# OpenTallas memory compiler (tools/mem_compiler), ASAP7 abstract view
VERSION 5.7 ;
BUSBITCHARS "[]" ;
DIVIDERCHAR "/" ;
PROPERTYDEFINITIONS
  MACRO width INTEGER ;
  MACRO depth INTEGER ;
  MACRO banks INTEGER ;
END PROPERTYDEFINITIONS
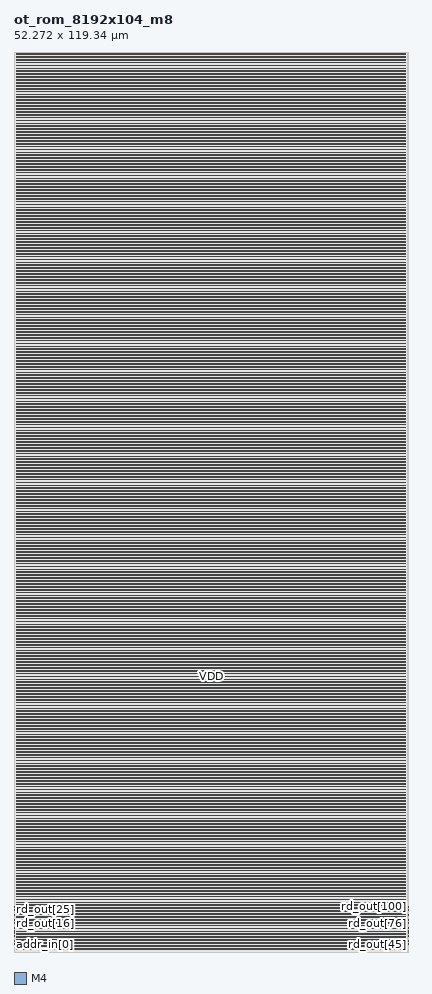
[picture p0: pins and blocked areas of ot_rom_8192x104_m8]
MACRO ot_rom_8192x104_m8
  PROPERTY width 104 ;
  PROPERTY depth 8192 ;
  PROPERTY banks 1 ;
  FOREIGN ot_rom_8192x104_m8 0 0 ;
  SYMMETRY X Y R90 ;
  SIZE 52.272 BY 119.340 ;
  CLASS BLOCK ;
  PIN clk
    DIRECTION INPUT ;
    USE CLOCK ;
    SHAPE ABUTMENT ;
    PORT
      LAYER M4 ;
      RECT 0.000 0.768 0.024 0.792 ;
    END
  END clk
  PIN ce_in
    DIRECTION INPUT ;
    USE SIGNAL ;
    SHAPE ABUTMENT ;
    PORT
      LAYER M4 ;
      RECT 0.000 0.864 0.024 0.888 ;
    END
  END ce_in
  PIN addr_in[0]
    DIRECTION INPUT ;
    USE SIGNAL ;
    SHAPE ABUTMENT ;
    PORT
      LAYER M4 ;
      RECT 0.000 0.960 0.024 0.984 ;
    END
  END addr_in[0]
  PIN addr_in[1]
    DIRECTION INPUT ;
    USE SIGNAL ;
    SHAPE ABUTMENT ;
    PORT
      LAYER M4 ;
      RECT 0.000 1.056 0.024 1.080 ;
    END
  END addr_in[1]
  PIN addr_in[2]
    DIRECTION INPUT ;
    USE SIGNAL ;
    SHAPE ABUTMENT ;
    PORT
      LAYER M4 ;
      RECT 0.000 1.152 0.024 1.176 ;
    END
  END addr_in[2]
  PIN addr_in[3]
    DIRECTION INPUT ;
    USE SIGNAL ;
    SHAPE ABUTMENT ;
    PORT
      LAYER M4 ;
      RECT 0.000 1.248 0.024 1.272 ;
    END
  END addr_in[3]
  PIN addr_in[4]
    DIRECTION INPUT ;
    USE SIGNAL ;
    SHAPE ABUTMENT ;
    PORT
      LAYER M4 ;
      RECT 0.000 1.344 0.024 1.368 ;
    END
  END addr_in[4]
  PIN addr_in[5]
    DIRECTION INPUT ;
    USE SIGNAL ;
    SHAPE ABUTMENT ;
    PORT
      LAYER M4 ;
      RECT 0.000 1.440 0.024 1.464 ;
    END
  END addr_in[5]
  PIN addr_in[6]
    DIRECTION INPUT ;
    USE SIGNAL ;
    SHAPE ABUTMENT ;
    PORT
      LAYER M4 ;
      RECT 0.000 1.536 0.024 1.560 ;
    END
  END addr_in[6]
  PIN addr_in[7]
    DIRECTION INPUT ;
    USE SIGNAL ;
    SHAPE ABUTMENT ;
    PORT
      LAYER M4 ;
      RECT 0.000 1.632 0.024 1.656 ;
    END
  END addr_in[7]
  PIN addr_in[8]
    DIRECTION INPUT ;
    USE SIGNAL ;
    SHAPE ABUTMENT ;
    PORT
      LAYER M4 ;
      RECT 0.000 1.728 0.024 1.752 ;
    END
  END addr_in[8]
  PIN addr_in[9]
    DIRECTION INPUT ;
    USE SIGNAL ;
    SHAPE ABUTMENT ;
    PORT
      LAYER M4 ;
      RECT 0.000 1.824 0.024 1.848 ;
    END
  END addr_in[9]
  PIN addr_in[10]
    DIRECTION INPUT ;
    USE SIGNAL ;
    SHAPE ABUTMENT ;
    PORT
      LAYER M4 ;
      RECT 0.000 1.920 0.024 1.944 ;
    END
  END addr_in[10]
  PIN addr_in[11]
    DIRECTION INPUT ;
    USE SIGNAL ;
    SHAPE ABUTMENT ;
    PORT
      LAYER M4 ;
      RECT 0.000 2.016 0.024 2.040 ;
    END
  END addr_in[11]
  PIN addr_in[12]
    DIRECTION INPUT ;
    USE SIGNAL ;
    SHAPE ABUTMENT ;
    PORT
      LAYER M4 ;
      RECT 0.000 2.112 0.024 2.136 ;
    END
  END addr_in[12]
  PIN rd_out[0]
    DIRECTION OUTPUT ;
    USE SIGNAL ;
    SHAPE ABUTMENT ;
    PORT
      LAYER M4 ;
      RECT 0.000 2.208 0.024 2.232 ;
    END
  END rd_out[0]
  PIN rd_out[1]
    DIRECTION OUTPUT ;
    USE SIGNAL ;
    SHAPE ABUTMENT ;
    PORT
      LAYER M4 ;
      RECT 0.000 2.304 0.024 2.328 ;
    END
  END rd_out[1]
  PIN rd_out[2]
    DIRECTION OUTPUT ;
    USE SIGNAL ;
    SHAPE ABUTMENT ;
    PORT
      LAYER M4 ;
      RECT 0.000 2.400 0.024 2.424 ;
    END
  END rd_out[2]
  PIN rd_out[3]
    DIRECTION OUTPUT ;
    USE SIGNAL ;
    SHAPE ABUTMENT ;
    PORT
      LAYER M4 ;
      RECT 0.000 2.496 0.024 2.520 ;
    END
  END rd_out[3]
  PIN rd_out[4]
    DIRECTION OUTPUT ;
    USE SIGNAL ;
    SHAPE ABUTMENT ;
    PORT
      LAYER M4 ;
      RECT 0.000 2.592 0.024 2.616 ;
    END
  END rd_out[4]
  PIN rd_out[5]
    DIRECTION OUTPUT ;
    USE SIGNAL ;
    SHAPE ABUTMENT ;
    PORT
      LAYER M4 ;
      RECT 0.000 2.688 0.024 2.712 ;
    END
  END rd_out[5]
  PIN rd_out[6]
    DIRECTION OUTPUT ;
    USE SIGNAL ;
    SHAPE ABUTMENT ;
    PORT
      LAYER M4 ;
      RECT 0.000 2.784 0.024 2.808 ;
    END
  END rd_out[6]
  PIN rd_out[7]
    DIRECTION OUTPUT ;
    USE SIGNAL ;
    SHAPE ABUTMENT ;
    PORT
      LAYER M4 ;
      RECT 0.000 2.880 0.024 2.904 ;
    END
  END rd_out[7]
  PIN rd_out[8]
    DIRECTION OUTPUT ;
    USE SIGNAL ;
    SHAPE ABUTMENT ;
    PORT
      LAYER M4 ;
      RECT 0.000 2.976 0.024 3.000 ;
    END
  END rd_out[8]
  PIN rd_out[9]
    DIRECTION OUTPUT ;
    USE SIGNAL ;
    SHAPE ABUTMENT ;
    PORT
      LAYER M4 ;
      RECT 0.000 3.072 0.024 3.096 ;
    END
  END rd_out[9]
  PIN rd_out[10]
    DIRECTION OUTPUT ;
    USE SIGNAL ;
    SHAPE ABUTMENT ;
    PORT
      LAYER M4 ;
      RECT 0.000 3.168 0.024 3.192 ;
    END
  END rd_out[10]
  PIN rd_out[11]
    DIRECTION OUTPUT ;
    USE SIGNAL ;
    SHAPE ABUTMENT ;
    PORT
      LAYER M4 ;
      RECT 0.000 3.264 0.024 3.288 ;
    END
  END rd_out[11]
  PIN rd_out[12]
    DIRECTION OUTPUT ;
    USE SIGNAL ;
    SHAPE ABUTMENT ;
    PORT
      LAYER M4 ;
      RECT 0.000 3.360 0.024 3.384 ;
    END
  END rd_out[12]
  PIN rd_out[13]
    DIRECTION OUTPUT ;
    USE SIGNAL ;
    SHAPE ABUTMENT ;
    PORT
      LAYER M4 ;
      RECT 0.000 3.456 0.024 3.480 ;
    END
  END rd_out[13]
  PIN rd_out[14]
    DIRECTION OUTPUT ;
    USE SIGNAL ;
    SHAPE ABUTMENT ;
    PORT
      LAYER M4 ;
      RECT 0.000 3.552 0.024 3.576 ;
    END
  END rd_out[14]
  PIN rd_out[15]
    DIRECTION OUTPUT ;
    USE SIGNAL ;
    SHAPE ABUTMENT ;
    PORT
      LAYER M4 ;
      RECT 0.000 3.648 0.024 3.672 ;
    END
  END rd_out[15]
  PIN rd_out[16]
    DIRECTION OUTPUT ;
    USE SIGNAL ;
    SHAPE ABUTMENT ;
    PORT
      LAYER M4 ;
      RECT 0.000 3.744 0.024 3.768 ;
    END
  END rd_out[16]
  PIN rd_out[17]
    DIRECTION OUTPUT ;
    USE SIGNAL ;
    SHAPE ABUTMENT ;
    PORT
      LAYER M4 ;
      RECT 0.000 3.840 0.024 3.864 ;
    END
  END rd_out[17]
  PIN rd_out[18]
    DIRECTION OUTPUT ;
    USE SIGNAL ;
    SHAPE ABUTMENT ;
    PORT
      LAYER M4 ;
      RECT 0.000 3.936 0.024 3.960 ;
    END
  END rd_out[18]
  PIN rd_out[19]
    DIRECTION OUTPUT ;
    USE SIGNAL ;
    SHAPE ABUTMENT ;
    PORT
      LAYER M4 ;
      RECT 0.000 4.032 0.024 4.056 ;
    END
  END rd_out[19]
  PIN rd_out[20]
    DIRECTION OUTPUT ;
    USE SIGNAL ;
    SHAPE ABUTMENT ;
    PORT
      LAYER M4 ;
      RECT 0.000 4.128 0.024 4.152 ;
    END
  END rd_out[20]
  PIN rd_out[21]
    DIRECTION OUTPUT ;
    USE SIGNAL ;
    SHAPE ABUTMENT ;
    PORT
      LAYER M4 ;
      RECT 0.000 4.224 0.024 4.248 ;
    END
  END rd_out[21]
  PIN rd_out[22]
    DIRECTION OUTPUT ;
    USE SIGNAL ;
    SHAPE ABUTMENT ;
    PORT
      LAYER M4 ;
      RECT 0.000 4.320 0.024 4.344 ;
    END
  END rd_out[22]
  PIN rd_out[23]
    DIRECTION OUTPUT ;
    USE SIGNAL ;
    SHAPE ABUTMENT ;
    PORT
      LAYER M4 ;
      RECT 0.000 4.416 0.024 4.440 ;
    END
  END rd_out[23]
  PIN rd_out[24]
    DIRECTION OUTPUT ;
    USE SIGNAL ;
    SHAPE ABUTMENT ;
    PORT
      LAYER M4 ;
      RECT 0.000 4.512 0.024 4.536 ;
    END
  END rd_out[24]
  PIN rd_out[25]
    DIRECTION OUTPUT ;
    USE SIGNAL ;
    SHAPE ABUTMENT ;
    PORT
      LAYER M4 ;
      RECT 0.000 4.608 0.024 4.632 ;
    END
  END rd_out[25]
  PIN rd_out[26]
    DIRECTION OUTPUT ;
    USE SIGNAL ;
    SHAPE ABUTMENT ;
    PORT
      LAYER M4 ;
      RECT 0.000 4.704 0.024 4.728 ;
    END
  END rd_out[26]
  PIN rd_out[27]
    DIRECTION OUTPUT ;
    USE SIGNAL ;
    SHAPE ABUTMENT ;
    PORT
      LAYER M4 ;
      RECT 0.000 4.800 0.024 4.824 ;
    END
  END rd_out[27]
  PIN rd_out[28]
    DIRECTION OUTPUT ;
    USE SIGNAL ;
    SHAPE ABUTMENT ;
    PORT
      LAYER M4 ;
      RECT 0.000 4.896 0.024 4.920 ;
    END
  END rd_out[28]
  PIN rd_out[29]
    DIRECTION OUTPUT ;
    USE SIGNAL ;
    SHAPE ABUTMENT ;
    PORT
      LAYER M4 ;
      RECT 0.000 4.992 0.024 5.016 ;
    END
  END rd_out[29]
  PIN rd_out[30]
    DIRECTION OUTPUT ;
    USE SIGNAL ;
    SHAPE ABUTMENT ;
    PORT
      LAYER M4 ;
      RECT 0.000 5.088 0.024 5.112 ;
    END
  END rd_out[30]
  PIN rd_out[31]
    DIRECTION OUTPUT ;
    USE SIGNAL ;
    SHAPE ABUTMENT ;
    PORT
      LAYER M4 ;
      RECT 0.000 5.184 0.024 5.208 ;
    END
  END rd_out[31]
  PIN rd_out[32]
    DIRECTION OUTPUT ;
    USE SIGNAL ;
    SHAPE ABUTMENT ;
    PORT
      LAYER M4 ;
      RECT 0.000 5.280 0.024 5.304 ;
    END
  END rd_out[32]
  PIN rd_out[33]
    DIRECTION OUTPUT ;
    USE SIGNAL ;
    SHAPE ABUTMENT ;
    PORT
      LAYER M4 ;
      RECT 0.000 5.376 0.024 5.400 ;
    END
  END rd_out[33]
  PIN rd_out[34]
    DIRECTION OUTPUT ;
    USE SIGNAL ;
    SHAPE ABUTMENT ;
    PORT
      LAYER M4 ;
      RECT 0.000 5.472 0.024 5.496 ;
    END
  END rd_out[34]
  PIN rd_out[35]
    DIRECTION OUTPUT ;
    USE SIGNAL ;
    SHAPE ABUTMENT ;
    PORT
      LAYER M4 ;
      RECT 0.000 5.568 0.024 5.592 ;
    END
  END rd_out[35]
  PIN rd_out[36]
    DIRECTION OUTPUT ;
    USE SIGNAL ;
    SHAPE ABUTMENT ;
    PORT
      LAYER M4 ;
      RECT 0.000 5.664 0.024 5.688 ;
    END
  END rd_out[36]
  PIN rd_out[37]
    DIRECTION OUTPUT ;
    USE SIGNAL ;
    SHAPE ABUTMENT ;
    PORT
      LAYER M4 ;
      RECT 0.000 5.760 0.024 5.784 ;
    END
  END rd_out[37]
  PIN rd_out[38]
    DIRECTION OUTPUT ;
    USE SIGNAL ;
    SHAPE ABUTMENT ;
    PORT
      LAYER M4 ;
      RECT 0.000 5.856 0.024 5.880 ;
    END
  END rd_out[38]
  PIN rd_out[39]
    DIRECTION OUTPUT ;
    USE SIGNAL ;
    SHAPE ABUTMENT ;
    PORT
      LAYER M4 ;
      RECT 0.000 5.952 0.024 5.976 ;
    END
  END rd_out[39]
  PIN rd_out[40]
    DIRECTION OUTPUT ;
    USE SIGNAL ;
    SHAPE ABUTMENT ;
    PORT
      LAYER M4 ;
      RECT 0.000 6.048 0.024 6.072 ;
    END
  END rd_out[40]
  PIN rd_out[41]
    DIRECTION OUTPUT ;
    USE SIGNAL ;
    SHAPE ABUTMENT ;
    PORT
      LAYER M4 ;
      RECT 0.000 6.144 0.024 6.168 ;
    END
  END rd_out[41]
  PIN rd_out[42]
    DIRECTION OUTPUT ;
    USE SIGNAL ;
    SHAPE ABUTMENT ;
    PORT
      LAYER M4 ;
      RECT 0.000 6.240 0.024 6.264 ;
    END
  END rd_out[42]
  PIN rd_out[43]
    DIRECTION OUTPUT ;
    USE SIGNAL ;
    SHAPE ABUTMENT ;
    PORT
      LAYER M4 ;
      RECT 0.000 6.336 0.024 6.360 ;
    END
  END rd_out[43]
  PIN rd_out[44]
    DIRECTION OUTPUT ;
    USE SIGNAL ;
    SHAPE ABUTMENT ;
    PORT
      LAYER M4 ;
      RECT 0.000 6.432 0.024 6.456 ;
    END
  END rd_out[44]
  PIN rd_out[45]
    DIRECTION OUTPUT ;
    USE SIGNAL ;
    SHAPE ABUTMENT ;
    PORT
      LAYER M4 ;
      RECT 52.248 0.768 52.272 0.792 ;
    END
  END rd_out[45]
  PIN rd_out[46]
    DIRECTION OUTPUT ;
    USE SIGNAL ;
    SHAPE ABUTMENT ;
    PORT
      LAYER M4 ;
      RECT 52.248 0.864 52.272 0.888 ;
    END
  END rd_out[46]
  PIN rd_out[47]
    DIRECTION OUTPUT ;
    USE SIGNAL ;
    SHAPE ABUTMENT ;
    PORT
      LAYER M4 ;
      RECT 52.248 0.960 52.272 0.984 ;
    END
  END rd_out[47]
  PIN rd_out[48]
    DIRECTION OUTPUT ;
    USE SIGNAL ;
    SHAPE ABUTMENT ;
    PORT
      LAYER M4 ;
      RECT 52.248 1.056 52.272 1.080 ;
    END
  END rd_out[48]
  PIN rd_out[49]
    DIRECTION OUTPUT ;
    USE SIGNAL ;
    SHAPE ABUTMENT ;
    PORT
      LAYER M4 ;
      RECT 52.248 1.152 52.272 1.176 ;
    END
  END rd_out[49]
  PIN rd_out[50]
    DIRECTION OUTPUT ;
    USE SIGNAL ;
    SHAPE ABUTMENT ;
    PORT
      LAYER M4 ;
      RECT 52.248 1.248 52.272 1.272 ;
    END
  END rd_out[50]
  PIN rd_out[51]
    DIRECTION OUTPUT ;
    USE SIGNAL ;
    SHAPE ABUTMENT ;
    PORT
      LAYER M4 ;
      RECT 52.248 1.344 52.272 1.368 ;
    END
  END rd_out[51]
  PIN rd_out[52]
    DIRECTION OUTPUT ;
    USE SIGNAL ;
    SHAPE ABUTMENT ;
    PORT
      LAYER M4 ;
      RECT 52.248 1.440 52.272 1.464 ;
    END
  END rd_out[52]
  PIN rd_out[53]
    DIRECTION OUTPUT ;
    USE SIGNAL ;
    SHAPE ABUTMENT ;
    PORT
      LAYER M4 ;
      RECT 52.248 1.536 52.272 1.560 ;
    END
  END rd_out[53]
  PIN rd_out[54]
    DIRECTION OUTPUT ;
    USE SIGNAL ;
    SHAPE ABUTMENT ;
    PORT
      LAYER M4 ;
      RECT 52.248 1.632 52.272 1.656 ;
    END
  END rd_out[54]
  PIN rd_out[55]
    DIRECTION OUTPUT ;
    USE SIGNAL ;
    SHAPE ABUTMENT ;
    PORT
      LAYER M4 ;
      RECT 52.248 1.728 52.272 1.752 ;
    END
  END rd_out[55]
  PIN rd_out[56]
    DIRECTION OUTPUT ;
    USE SIGNAL ;
    SHAPE ABUTMENT ;
    PORT
      LAYER M4 ;
      RECT 52.248 1.824 52.272 1.848 ;
    END
  END rd_out[56]
  PIN rd_out[57]
    DIRECTION OUTPUT ;
    USE SIGNAL ;
    SHAPE ABUTMENT ;
    PORT
      LAYER M4 ;
      RECT 52.248 1.920 52.272 1.944 ;
    END
  END rd_out[57]
  PIN rd_out[58]
    DIRECTION OUTPUT ;
    USE SIGNAL ;
    SHAPE ABUTMENT ;
    PORT
      LAYER M4 ;
      RECT 52.248 2.016 52.272 2.040 ;
    END
  END rd_out[58]
  PIN rd_out[59]
    DIRECTION OUTPUT ;
    USE SIGNAL ;
    SHAPE ABUTMENT ;
    PORT
      LAYER M4 ;
      RECT 52.248 2.112 52.272 2.136 ;
    END
  END rd_out[59]
  PIN rd_out[60]
    DIRECTION OUTPUT ;
    USE SIGNAL ;
    SHAPE ABUTMENT ;
    PORT
      LAYER M4 ;
      RECT 52.248 2.208 52.272 2.232 ;
    END
  END rd_out[60]
  PIN rd_out[61]
    DIRECTION OUTPUT ;
    USE SIGNAL ;
    SHAPE ABUTMENT ;
    PORT
      LAYER M4 ;
      RECT 52.248 2.304 52.272 2.328 ;
    END
  END rd_out[61]
  PIN rd_out[62]
    DIRECTION OUTPUT ;
    USE SIGNAL ;
    SHAPE ABUTMENT ;
    PORT
      LAYER M4 ;
      RECT 52.248 2.400 52.272 2.424 ;
    END
  END rd_out[62]
  PIN rd_out[63]
    DIRECTION OUTPUT ;
    USE SIGNAL ;
    SHAPE ABUTMENT ;
    PORT
      LAYER M4 ;
      RECT 52.248 2.496 52.272 2.520 ;
    END
  END rd_out[63]
  PIN rd_out[64]
    DIRECTION OUTPUT ;
    USE SIGNAL ;
    SHAPE ABUTMENT ;
    PORT
      LAYER M4 ;
      RECT 52.248 2.592 52.272 2.616 ;
    END
  END rd_out[64]
  PIN rd_out[65]
    DIRECTION OUTPUT ;
    USE SIGNAL ;
    SHAPE ABUTMENT ;
    PORT
      LAYER M4 ;
      RECT 52.248 2.688 52.272 2.712 ;
    END
  END rd_out[65]
  PIN rd_out[66]
    DIRECTION OUTPUT ;
    USE SIGNAL ;
    SHAPE ABUTMENT ;
    PORT
      LAYER M4 ;
      RECT 52.248 2.784 52.272 2.808 ;
    END
  END rd_out[66]
  PIN rd_out[67]
    DIRECTION OUTPUT ;
    USE SIGNAL ;
    SHAPE ABUTMENT ;
    PORT
      LAYER M4 ;
      RECT 52.248 2.880 52.272 2.904 ;
    END
  END rd_out[67]
  PIN rd_out[68]
    DIRECTION OUTPUT ;
    USE SIGNAL ;
    SHAPE ABUTMENT ;
    PORT
      LAYER M4 ;
      RECT 52.248 2.976 52.272 3.000 ;
    END
  END rd_out[68]
  PIN rd_out[69]
    DIRECTION OUTPUT ;
    USE SIGNAL ;
    SHAPE ABUTMENT ;
    PORT
      LAYER M4 ;
      RECT 52.248 3.072 52.272 3.096 ;
    END
  END rd_out[69]
  PIN rd_out[70]
    DIRECTION OUTPUT ;
    USE SIGNAL ;
    SHAPE ABUTMENT ;
    PORT
      LAYER M4 ;
      RECT 52.248 3.168 52.272 3.192 ;
    END
  END rd_out[70]
  PIN rd_out[71]
    DIRECTION OUTPUT ;
    USE SIGNAL ;
    SHAPE ABUTMENT ;
    PORT
      LAYER M4 ;
      RECT 52.248 3.264 52.272 3.288 ;
    END
  END rd_out[71]
  PIN rd_out[72]
    DIRECTION OUTPUT ;
    USE SIGNAL ;
    SHAPE ABUTMENT ;
    PORT
      LAYER M4 ;
      RECT 52.248 3.360 52.272 3.384 ;
    END
  END rd_out[72]
  PIN rd_out[73]
    DIRECTION OUTPUT ;
    USE SIGNAL ;
    SHAPE ABUTMENT ;
    PORT
      LAYER M4 ;
      RECT 52.248 3.456 52.272 3.480 ;
    END
  END rd_out[73]
  PIN rd_out[74]
    DIRECTION OUTPUT ;
    USE SIGNAL ;
    SHAPE ABUTMENT ;
    PORT
      LAYER M4 ;
      RECT 52.248 3.552 52.272 3.576 ;
    END
  END rd_out[74]
  PIN rd_out[75]
    DIRECTION OUTPUT ;
    USE SIGNAL ;
    SHAPE ABUTMENT ;
    PORT
      LAYER M4 ;
      RECT 52.248 3.648 52.272 3.672 ;
    END
  END rd_out[75]
  PIN rd_out[76]
    DIRECTION OUTPUT ;
    USE SIGNAL ;
    SHAPE ABUTMENT ;
    PORT
      LAYER M4 ;
      RECT 52.248 3.744 52.272 3.768 ;
    END
  END rd_out[76]
  PIN rd_out[77]
    DIRECTION OUTPUT ;
    USE SIGNAL ;
    SHAPE ABUTMENT ;
    PORT
      LAYER M4 ;
      RECT 52.248 3.840 52.272 3.864 ;
    END
  END rd_out[77]
  PIN rd_out[78]
    DIRECTION OUTPUT ;
    USE SIGNAL ;
    SHAPE ABUTMENT ;
    PORT
      LAYER M4 ;
      RECT 52.248 3.936 52.272 3.960 ;
    END
  END rd_out[78]
  PIN rd_out[79]
    DIRECTION OUTPUT ;
    USE SIGNAL ;
    SHAPE ABUTMENT ;
    PORT
      LAYER M4 ;
      RECT 52.248 4.032 52.272 4.056 ;
    END
  END rd_out[79]
  PIN rd_out[80]
    DIRECTION OUTPUT ;
    USE SIGNAL ;
    SHAPE ABUTMENT ;
    PORT
      LAYER M4 ;
      RECT 52.248 4.128 52.272 4.152 ;
    END
  END rd_out[80]
  PIN rd_out[81]
    DIRECTION OUTPUT ;
    USE SIGNAL ;
    SHAPE ABUTMENT ;
    PORT
      LAYER M4 ;
      RECT 52.248 4.224 52.272 4.248 ;
    END
  END rd_out[81]
  PIN rd_out[82]
    DIRECTION OUTPUT ;
    USE SIGNAL ;
    SHAPE ABUTMENT ;
    PORT
      LAYER M4 ;
      RECT 52.248 4.320 52.272 4.344 ;
    END
  END rd_out[82]
  PIN rd_out[83]
    DIRECTION OUTPUT ;
    USE SIGNAL ;
    SHAPE ABUTMENT ;
    PORT
      LAYER M4 ;
      RECT 52.248 4.416 52.272 4.440 ;
    END
  END rd_out[83]
  PIN rd_out[84]
    DIRECTION OUTPUT ;
    USE SIGNAL ;
    SHAPE ABUTMENT ;
    PORT
      LAYER M4 ;
      RECT 52.248 4.512 52.272 4.536 ;
    END
  END rd_out[84]
  PIN rd_out[85]
    DIRECTION OUTPUT ;
    USE SIGNAL ;
    SHAPE ABUTMENT ;
    PORT
      LAYER M4 ;
      RECT 52.248 4.608 52.272 4.632 ;
    END
  END rd_out[85]
  PIN rd_out[86]
    DIRECTION OUTPUT ;
    USE SIGNAL ;
    SHAPE ABUTMENT ;
    PORT
      LAYER M4 ;
      RECT 52.248 4.704 52.272 4.728 ;
    END
  END rd_out[86]
  PIN rd_out[87]
    DIRECTION OUTPUT ;
    USE SIGNAL ;
    SHAPE ABUTMENT ;
    PORT
      LAYER M4 ;
      RECT 52.248 4.800 52.272 4.824 ;
    END
  END rd_out[87]
  PIN rd_out[88]
    DIRECTION OUTPUT ;
    USE SIGNAL ;
    SHAPE ABUTMENT ;
    PORT
      LAYER M4 ;
      RECT 52.248 4.896 52.272 4.920 ;
    END
  END rd_out[88]
  PIN rd_out[89]
    DIRECTION OUTPUT ;
    USE SIGNAL ;
    SHAPE ABUTMENT ;
    PORT
      LAYER M4 ;
      RECT 52.248 4.992 52.272 5.016 ;
    END
  END rd_out[89]
  PIN rd_out[90]
    DIRECTION OUTPUT ;
    USE SIGNAL ;
    SHAPE ABUTMENT ;
    PORT
      LAYER M4 ;
      RECT 52.248 5.088 52.272 5.112 ;
    END
  END rd_out[90]
  PIN rd_out[91]
    DIRECTION OUTPUT ;
    USE SIGNAL ;
    SHAPE ABUTMENT ;
    PORT
      LAYER M4 ;
      RECT 52.248 5.184 52.272 5.208 ;
    END
  END rd_out[91]
  PIN rd_out[92]
    DIRECTION OUTPUT ;
    USE SIGNAL ;
    SHAPE ABUTMENT ;
    PORT
      LAYER M4 ;
      RECT 52.248 5.280 52.272 5.304 ;
    END
  END rd_out[92]
  PIN rd_out[93]
    DIRECTION OUTPUT ;
    USE SIGNAL ;
    SHAPE ABUTMENT ;
    PORT
      LAYER M4 ;
      RECT 52.248 5.376 52.272 5.400 ;
    END
  END rd_out[93]
  PIN rd_out[94]
    DIRECTION OUTPUT ;
    USE SIGNAL ;
    SHAPE ABUTMENT ;
    PORT
      LAYER M4 ;
      RECT 52.248 5.472 52.272 5.496 ;
    END
  END rd_out[94]
  PIN rd_out[95]
    DIRECTION OUTPUT ;
    USE SIGNAL ;
    SHAPE ABUTMENT ;
    PORT
      LAYER M4 ;
      RECT 52.248 5.568 52.272 5.592 ;
    END
  END rd_out[95]
  PIN rd_out[96]
    DIRECTION OUTPUT ;
    USE SIGNAL ;
    SHAPE ABUTMENT ;
    PORT
      LAYER M4 ;
      RECT 52.248 5.664 52.272 5.688 ;
    END
  END rd_out[96]
  PIN rd_out[97]
    DIRECTION OUTPUT ;
    USE SIGNAL ;
    SHAPE ABUTMENT ;
    PORT
      LAYER M4 ;
      RECT 52.248 5.760 52.272 5.784 ;
    END
  END rd_out[97]
  PIN rd_out[98]
    DIRECTION OUTPUT ;
    USE SIGNAL ;
    SHAPE ABUTMENT ;
    PORT
      LAYER M4 ;
      RECT 52.248 5.856 52.272 5.880 ;
    END
  END rd_out[98]
  PIN rd_out[99]
    DIRECTION OUTPUT ;
    USE SIGNAL ;
    SHAPE ABUTMENT ;
    PORT
      LAYER M4 ;
      RECT 52.248 5.952 52.272 5.976 ;
    END
  END rd_out[99]
  PIN rd_out[100]
    DIRECTION OUTPUT ;
    USE SIGNAL ;
    SHAPE ABUTMENT ;
    PORT
      LAYER M4 ;
      RECT 52.248 6.048 52.272 6.072 ;
    END
  END rd_out[100]
  PIN rd_out[101]
    DIRECTION OUTPUT ;
    USE SIGNAL ;
    SHAPE ABUTMENT ;
    PORT
      LAYER M4 ;
      RECT 52.248 6.144 52.272 6.168 ;
    END
  END rd_out[101]
  PIN rd_out[102]
    DIRECTION OUTPUT ;
    USE SIGNAL ;
    SHAPE ABUTMENT ;
    PORT
      LAYER M4 ;
      RECT 52.248 6.240 52.272 6.264 ;
    END
  END rd_out[102]
  PIN rd_out[103]
    DIRECTION OUTPUT ;
    USE SIGNAL ;
    SHAPE ABUTMENT ;
    PORT
      LAYER M4 ;
      RECT 52.248 6.336 52.272 6.360 ;
    END
  END rd_out[103]
  PIN VDD
    DIRECTION INOUT ;
    USE POWER ;
    PORT
      LAYER M4 ;
      RECT 0.300 0.384 51.972 0.480 ;
      RECT 0.300 1.152 51.972 1.248 ;
      RECT 0.300 1.920 51.972 2.016 ;
      RECT 0.300 2.688 51.972 2.784 ;
      RECT 0.300 3.456 51.972 3.552 ;
      RECT 0.300 4.224 51.972 4.320 ;
      RECT 0.300 4.992 51.972 5.088 ;
      RECT 0.300 5.760 51.972 5.856 ;
      RECT 0.300 6.528 51.972 6.624 ;
      RECT 0.300 7.296 51.972 7.392 ;
      RECT 0.300 8.064 51.972 8.160 ;
      RECT 0.300 8.832 51.972 8.928 ;
      RECT 0.300 9.600 51.972 9.696 ;
      RECT 0.300 10.368 51.972 10.464 ;
      RECT 0.300 11.136 51.972 11.232 ;
      RECT 0.300 11.904 51.972 12.000 ;
      RECT 0.300 12.672 51.972 12.768 ;
      RECT 0.300 13.440 51.972 13.536 ;
      RECT 0.300 14.208 51.972 14.304 ;
      RECT 0.300 14.976 51.972 15.072 ;
      RECT 0.300 15.744 51.972 15.840 ;
      RECT 0.300 16.512 51.972 16.608 ;
      RECT 0.300 17.280 51.972 17.376 ;
      RECT 0.300 18.048 51.972 18.144 ;
      RECT 0.300 18.816 51.972 18.912 ;
      RECT 0.300 19.584 51.972 19.680 ;
      RECT 0.300 20.352 51.972 20.448 ;
      RECT 0.300 21.120 51.972 21.216 ;
      RECT 0.300 21.888 51.972 21.984 ;
      RECT 0.300 22.656 51.972 22.752 ;
      RECT 0.300 23.424 51.972 23.520 ;
      RECT 0.300 24.192 51.972 24.288 ;
      RECT 0.300 24.960 51.972 25.056 ;
      RECT 0.300 25.728 51.972 25.824 ;
      RECT 0.300 26.496 51.972 26.592 ;
      RECT 0.300 27.264 51.972 27.360 ;
      RECT 0.300 28.032 51.972 28.128 ;
      RECT 0.300 28.800 51.972 28.896 ;
      RECT 0.300 29.568 51.972 29.664 ;
      RECT 0.300 30.336 51.972 30.432 ;
      RECT 0.300 31.104 51.972 31.200 ;
      RECT 0.300 31.872 51.972 31.968 ;
      RECT 0.300 32.640 51.972 32.736 ;
      RECT 0.300 33.408 51.972 33.504 ;
      RECT 0.300 34.176 51.972 34.272 ;
      RECT 0.300 34.944 51.972 35.040 ;
      RECT 0.300 35.712 51.972 35.808 ;
      RECT 0.300 36.480 51.972 36.576 ;
      RECT 0.300 37.248 51.972 37.344 ;
      RECT 0.300 38.016 51.972 38.112 ;
      RECT 0.300 38.784 51.972 38.880 ;
      RECT 0.300 39.552 51.972 39.648 ;
      RECT 0.300 40.320 51.972 40.416 ;
      RECT 0.300 41.088 51.972 41.184 ;
      RECT 0.300 41.856 51.972 41.952 ;
      RECT 0.300 42.624 51.972 42.720 ;
      RECT 0.300 43.392 51.972 43.488 ;
      RECT 0.300 44.160 51.972 44.256 ;
      RECT 0.300 44.928 51.972 45.024 ;
      RECT 0.300 45.696 51.972 45.792 ;
      RECT 0.300 46.464 51.972 46.560 ;
      RECT 0.300 47.232 51.972 47.328 ;
      RECT 0.300 48.000 51.972 48.096 ;
      RECT 0.300 48.768 51.972 48.864 ;
      RECT 0.300 49.536 51.972 49.632 ;
      RECT 0.300 50.304 51.972 50.400 ;
      RECT 0.300 51.072 51.972 51.168 ;
      RECT 0.300 51.840 51.972 51.936 ;
      RECT 0.300 52.608 51.972 52.704 ;
      RECT 0.300 53.376 51.972 53.472 ;
      RECT 0.300 54.144 51.972 54.240 ;
      RECT 0.300 54.912 51.972 55.008 ;
      RECT 0.300 55.680 51.972 55.776 ;
      RECT 0.300 56.448 51.972 56.544 ;
      RECT 0.300 57.216 51.972 57.312 ;
      RECT 0.300 57.984 51.972 58.080 ;
      RECT 0.300 58.752 51.972 58.848 ;
      RECT 0.300 59.520 51.972 59.616 ;
      RECT 0.300 60.288 51.972 60.384 ;
      RECT 0.300 61.056 51.972 61.152 ;
      RECT 0.300 61.824 51.972 61.920 ;
      RECT 0.300 62.592 51.972 62.688 ;
      RECT 0.300 63.360 51.972 63.456 ;
      RECT 0.300 64.128 51.972 64.224 ;
      RECT 0.300 64.896 51.972 64.992 ;
      RECT 0.300 65.664 51.972 65.760 ;
      RECT 0.300 66.432 51.972 66.528 ;
      RECT 0.300 67.200 51.972 67.296 ;
      RECT 0.300 67.968 51.972 68.064 ;
      RECT 0.300 68.736 51.972 68.832 ;
      RECT 0.300 69.504 51.972 69.600 ;
      RECT 0.300 70.272 51.972 70.368 ;
      RECT 0.300 71.040 51.972 71.136 ;
      RECT 0.300 71.808 51.972 71.904 ;
      RECT 0.300 72.576 51.972 72.672 ;
      RECT 0.300 73.344 51.972 73.440 ;
      RECT 0.300 74.112 51.972 74.208 ;
      RECT 0.300 74.880 51.972 74.976 ;
      RECT 0.300 75.648 51.972 75.744 ;
      RECT 0.300 76.416 51.972 76.512 ;
      RECT 0.300 77.184 51.972 77.280 ;
      RECT 0.300 77.952 51.972 78.048 ;
      RECT 0.300 78.720 51.972 78.816 ;
      RECT 0.300 79.488 51.972 79.584 ;
      RECT 0.300 80.256 51.972 80.352 ;
      RECT 0.300 81.024 51.972 81.120 ;
      RECT 0.300 81.792 51.972 81.888 ;
      RECT 0.300 82.560 51.972 82.656 ;
      RECT 0.300 83.328 51.972 83.424 ;
      RECT 0.300 84.096 51.972 84.192 ;
      RECT 0.300 84.864 51.972 84.960 ;
      RECT 0.300 85.632 51.972 85.728 ;
      RECT 0.300 86.400 51.972 86.496 ;
      RECT 0.300 87.168 51.972 87.264 ;
      RECT 0.300 87.936 51.972 88.032 ;
      RECT 0.300 88.704 51.972 88.800 ;
      RECT 0.300 89.472 51.972 89.568 ;
      RECT 0.300 90.240 51.972 90.336 ;
      RECT 0.300 91.008 51.972 91.104 ;
      RECT 0.300 91.776 51.972 91.872 ;
      RECT 0.300 92.544 51.972 92.640 ;
      RECT 0.300 93.312 51.972 93.408 ;
      RECT 0.300 94.080 51.972 94.176 ;
      RECT 0.300 94.848 51.972 94.944 ;
      RECT 0.300 95.616 51.972 95.712 ;
      RECT 0.300 96.384 51.972 96.480 ;
      RECT 0.300 97.152 51.972 97.248 ;
      RECT 0.300 97.920 51.972 98.016 ;
      RECT 0.300 98.688 51.972 98.784 ;
      RECT 0.300 99.456 51.972 99.552 ;
      RECT 0.300 100.224 51.972 100.320 ;
      RECT 0.300 100.992 51.972 101.088 ;
      RECT 0.300 101.760 51.972 101.856 ;
      RECT 0.300 102.528 51.972 102.624 ;
      RECT 0.300 103.296 51.972 103.392 ;
      RECT 0.300 104.064 51.972 104.160 ;
      RECT 0.300 104.832 51.972 104.928 ;
      RECT 0.300 105.600 51.972 105.696 ;
      RECT 0.300 106.368 51.972 106.464 ;
      RECT 0.300 107.136 51.972 107.232 ;
      RECT 0.300 107.904 51.972 108.000 ;
      RECT 0.300 108.672 51.972 108.768 ;
      RECT 0.300 109.440 51.972 109.536 ;
      RECT 0.300 110.208 51.972 110.304 ;
      RECT 0.300 110.976 51.972 111.072 ;
      RECT 0.300 111.744 51.972 111.840 ;
      RECT 0.300 112.512 51.972 112.608 ;
      RECT 0.300 113.280 51.972 113.376 ;
      RECT 0.300 114.048 51.972 114.144 ;
      RECT 0.300 114.816 51.972 114.912 ;
      RECT 0.300 115.584 51.972 115.680 ;
      RECT 0.300 116.352 51.972 116.448 ;
      RECT 0.300 117.120 51.972 117.216 ;
      RECT 0.300 117.888 51.972 117.984 ;
      RECT 0.300 118.656 51.972 118.752 ;
    END
  END VDD
  PIN VSS
    DIRECTION INOUT ;
    USE GROUND ;
    PORT
      LAYER M4 ;
      RECT 0.300 0.768 51.972 0.864 ;
      RECT 0.300 1.536 51.972 1.632 ;
      RECT 0.300 2.304 51.972 2.400 ;
      RECT 0.300 3.072 51.972 3.168 ;
      RECT 0.300 3.840 51.972 3.936 ;
      RECT 0.300 4.608 51.972 4.704 ;
      RECT 0.300 5.376 51.972 5.472 ;
      RECT 0.300 6.144 51.972 6.240 ;
      RECT 0.300 6.912 51.972 7.008 ;
      RECT 0.300 7.680 51.972 7.776 ;
      RECT 0.300 8.448 51.972 8.544 ;
      RECT 0.300 9.216 51.972 9.312 ;
      RECT 0.300 9.984 51.972 10.080 ;
      RECT 0.300 10.752 51.972 10.848 ;
      RECT 0.300 11.520 51.972 11.616 ;
      RECT 0.300 12.288 51.972 12.384 ;
      RECT 0.300 13.056 51.972 13.152 ;
      RECT 0.300 13.824 51.972 13.920 ;
      RECT 0.300 14.592 51.972 14.688 ;
      RECT 0.300 15.360 51.972 15.456 ;
      RECT 0.300 16.128 51.972 16.224 ;
      RECT 0.300 16.896 51.972 16.992 ;
      RECT 0.300 17.664 51.972 17.760 ;
      RECT 0.300 18.432 51.972 18.528 ;
      RECT 0.300 19.200 51.972 19.296 ;
      RECT 0.300 19.968 51.972 20.064 ;
      RECT 0.300 20.736 51.972 20.832 ;
      RECT 0.300 21.504 51.972 21.600 ;
      RECT 0.300 22.272 51.972 22.368 ;
      RECT 0.300 23.040 51.972 23.136 ;
      RECT 0.300 23.808 51.972 23.904 ;
      RECT 0.300 24.576 51.972 24.672 ;
      RECT 0.300 25.344 51.972 25.440 ;
      RECT 0.300 26.112 51.972 26.208 ;
      RECT 0.300 26.880 51.972 26.976 ;
      RECT 0.300 27.648 51.972 27.744 ;
      RECT 0.300 28.416 51.972 28.512 ;
      RECT 0.300 29.184 51.972 29.280 ;
      RECT 0.300 29.952 51.972 30.048 ;
      RECT 0.300 30.720 51.972 30.816 ;
      RECT 0.300 31.488 51.972 31.584 ;
      RECT 0.300 32.256 51.972 32.352 ;
      RECT 0.300 33.024 51.972 33.120 ;
      RECT 0.300 33.792 51.972 33.888 ;
      RECT 0.300 34.560 51.972 34.656 ;
      RECT 0.300 35.328 51.972 35.424 ;
      RECT 0.300 36.096 51.972 36.192 ;
      RECT 0.300 36.864 51.972 36.960 ;
      RECT 0.300 37.632 51.972 37.728 ;
      RECT 0.300 38.400 51.972 38.496 ;
      RECT 0.300 39.168 51.972 39.264 ;
      RECT 0.300 39.936 51.972 40.032 ;
      RECT 0.300 40.704 51.972 40.800 ;
      RECT 0.300 41.472 51.972 41.568 ;
      RECT 0.300 42.240 51.972 42.336 ;
      RECT 0.300 43.008 51.972 43.104 ;
      RECT 0.300 43.776 51.972 43.872 ;
      RECT 0.300 44.544 51.972 44.640 ;
      RECT 0.300 45.312 51.972 45.408 ;
      RECT 0.300 46.080 51.972 46.176 ;
      RECT 0.300 46.848 51.972 46.944 ;
      RECT 0.300 47.616 51.972 47.712 ;
      RECT 0.300 48.384 51.972 48.480 ;
      RECT 0.300 49.152 51.972 49.248 ;
      RECT 0.300 49.920 51.972 50.016 ;
      RECT 0.300 50.688 51.972 50.784 ;
      RECT 0.300 51.456 51.972 51.552 ;
      RECT 0.300 52.224 51.972 52.320 ;
      RECT 0.300 52.992 51.972 53.088 ;
      RECT 0.300 53.760 51.972 53.856 ;
      RECT 0.300 54.528 51.972 54.624 ;
      RECT 0.300 55.296 51.972 55.392 ;
      RECT 0.300 56.064 51.972 56.160 ;
      RECT 0.300 56.832 51.972 56.928 ;
      RECT 0.300 57.600 51.972 57.696 ;
      RECT 0.300 58.368 51.972 58.464 ;
      RECT 0.300 59.136 51.972 59.232 ;
      RECT 0.300 59.904 51.972 60.000 ;
      RECT 0.300 60.672 51.972 60.768 ;
      RECT 0.300 61.440 51.972 61.536 ;
      RECT 0.300 62.208 51.972 62.304 ;
      RECT 0.300 62.976 51.972 63.072 ;
      RECT 0.300 63.744 51.972 63.840 ;
      RECT 0.300 64.512 51.972 64.608 ;
      RECT 0.300 65.280 51.972 65.376 ;
      RECT 0.300 66.048 51.972 66.144 ;
      RECT 0.300 66.816 51.972 66.912 ;
      RECT 0.300 67.584 51.972 67.680 ;
      RECT 0.300 68.352 51.972 68.448 ;
      RECT 0.300 69.120 51.972 69.216 ;
      RECT 0.300 69.888 51.972 69.984 ;
      RECT 0.300 70.656 51.972 70.752 ;
      RECT 0.300 71.424 51.972 71.520 ;
      RECT 0.300 72.192 51.972 72.288 ;
      RECT 0.300 72.960 51.972 73.056 ;
      RECT 0.300 73.728 51.972 73.824 ;
      RECT 0.300 74.496 51.972 74.592 ;
      RECT 0.300 75.264 51.972 75.360 ;
      RECT 0.300 76.032 51.972 76.128 ;
      RECT 0.300 76.800 51.972 76.896 ;
      RECT 0.300 77.568 51.972 77.664 ;
      RECT 0.300 78.336 51.972 78.432 ;
      RECT 0.300 79.104 51.972 79.200 ;
      RECT 0.300 79.872 51.972 79.968 ;
      RECT 0.300 80.640 51.972 80.736 ;
      RECT 0.300 81.408 51.972 81.504 ;
      RECT 0.300 82.176 51.972 82.272 ;
      RECT 0.300 82.944 51.972 83.040 ;
      RECT 0.300 83.712 51.972 83.808 ;
      RECT 0.300 84.480 51.972 84.576 ;
      RECT 0.300 85.248 51.972 85.344 ;
      RECT 0.300 86.016 51.972 86.112 ;
      RECT 0.300 86.784 51.972 86.880 ;
      RECT 0.300 87.552 51.972 87.648 ;
      RECT 0.300 88.320 51.972 88.416 ;
      RECT 0.300 89.088 51.972 89.184 ;
      RECT 0.300 89.856 51.972 89.952 ;
      RECT 0.300 90.624 51.972 90.720 ;
      RECT 0.300 91.392 51.972 91.488 ;
      RECT 0.300 92.160 51.972 92.256 ;
      RECT 0.300 92.928 51.972 93.024 ;
      RECT 0.300 93.696 51.972 93.792 ;
      RECT 0.300 94.464 51.972 94.560 ;
      RECT 0.300 95.232 51.972 95.328 ;
      RECT 0.300 96.000 51.972 96.096 ;
      RECT 0.300 96.768 51.972 96.864 ;
      RECT 0.300 97.536 51.972 97.632 ;
      RECT 0.300 98.304 51.972 98.400 ;
      RECT 0.300 99.072 51.972 99.168 ;
      RECT 0.300 99.840 51.972 99.936 ;
      RECT 0.300 100.608 51.972 100.704 ;
      RECT 0.300 101.376 51.972 101.472 ;
      RECT 0.300 102.144 51.972 102.240 ;
      RECT 0.300 102.912 51.972 103.008 ;
      RECT 0.300 103.680 51.972 103.776 ;
      RECT 0.300 104.448 51.972 104.544 ;
      RECT 0.300 105.216 51.972 105.312 ;
      RECT 0.300 105.984 51.972 106.080 ;
      RECT 0.300 106.752 51.972 106.848 ;
      RECT 0.300 107.520 51.972 107.616 ;
      RECT 0.300 108.288 51.972 108.384 ;
      RECT 0.300 109.056 51.972 109.152 ;
      RECT 0.300 109.824 51.972 109.920 ;
      RECT 0.300 110.592 51.972 110.688 ;
      RECT 0.300 111.360 51.972 111.456 ;
      RECT 0.300 112.128 51.972 112.224 ;
      RECT 0.300 112.896 51.972 112.992 ;
      RECT 0.300 113.664 51.972 113.760 ;
      RECT 0.300 114.432 51.972 114.528 ;
      RECT 0.300 115.200 51.972 115.296 ;
      RECT 0.300 115.968 51.972 116.064 ;
      RECT 0.300 116.736 51.972 116.832 ;
      RECT 0.300 117.504 51.972 117.600 ;
      RECT 0.300 118.272 51.972 118.368 ;
      RECT 0.300 119.040 51.972 119.136 ;
    END
  END VSS
  OBS
    LAYER M1 ;
    RECT 0 0 52.272 119.340 ;
    LAYER M2 ;
    RECT 0 0 52.272 119.340 ;
    LAYER M3 ;
    RECT 0 0 52.272 119.340 ;
    LAYER M4 ;
    RECT 0.072 0 52.200 119.340 ;
  END
END ot_rom_8192x104_m8

END LIBRARY
